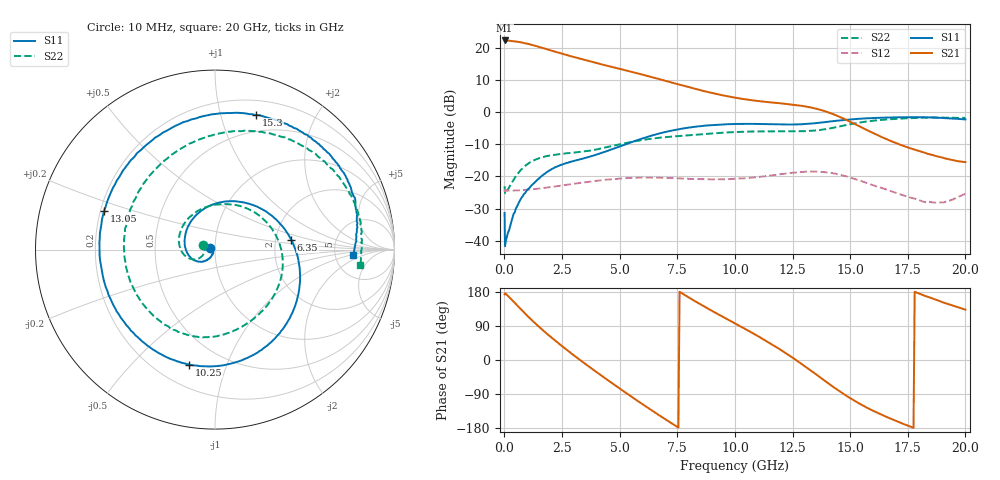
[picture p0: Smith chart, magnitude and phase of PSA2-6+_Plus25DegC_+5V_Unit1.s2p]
!Keysight Technologies,N5242A,MY47200155,A.10.49.08
!Date: Thursday, October 19, 2023 15:15:29
!Correction: S11(Full 2 Port(1,2))
!S21(Full 2 Port(1,2))
!S12(Full 2 Port(1,2))
!S22(Full 2 Port(1,2))
!S2P File: Measurements: S11, S21, S12, S22:
# Hz S  dB  R 50
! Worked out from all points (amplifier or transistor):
!   408 points, 10 MHz to 20 GHz, reference 50 ohm
!   highest |S21| = 22.3 dB at 10 MHz (marker M1)
!   |S21| within 3 dB of that: start of sweep to 1.969 GHz
!   unconditionally stable (mu >= 1): start of sweep to end of sweep
!   at 3.05 GHz: K = 1.07, MAG = 18.0 dB, |S12| = -22.2 dB
!   at 9.85 GHz: K = 1.32, MAG = 9.3 dB, |S12| = -20.8 dB
!   at 20 GHz: K = 7.22, MAG = -6.6 dB, |S12| = -25.4 dB
!   S11 on the Smith chart (normalised r, x): 10 MHz: 0.95, +0.02; 6.35 GHz: 2.44, +0.33; 10.25 GHz: 0.33, -0.75; 13.05 GHz: 0.21, +0.16; 15.3 GHz: 0.33, +1.29; 20 GHz: 7.54, -1.21
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1e7  -31.35 162.3  22.27 173.2  -24.74 -4.6  -23.01 157.6
7e7  -39.74 -163.0  22.22 174.4  -24.42 -1.7  -24.87 -174.5
3.5e8  -32.85 -122.4  22.09 156.8  -24.36 -5.6  -21.64 -152.9
7.5e8  -26.51 -119.2  21.64 131.6  -24.24 -11.4  -17.73 -154.9
1.3e9  -21.98 -130.0  20.69 98.9  -23.90 -20.2  -14.91 -173.1
1.8e9  -18.82 -143.8  19.63 71.7  -23.48 -28.9  -13.72 167.5
2.25e9  -17.02 -160.2  18.68 48.8  -23.03 -37.5  -13.19 149.0
2.75e9  -15.75 178.3  17.65 24.6  -22.54 -48.0  -12.78 127.6
3.35e9  -14.55 150.7  16.46 -3.1  -21.94 -61.7  -12.32 101.5
4e9  -13.20 118.6  15.25 -32.0  -21.35 -77.7  -11.60 74.1
4.7e9  -11.48 82.2  13.99 -62.4  -20.81 -96.2  -10.48 45.8
5.4e9  -9.65 48.0  12.74 -92.1  -20.48 -115.4  -9.42 19.7
6.35e9  -7.38 7.5  10.97 -131.3  -20.34 -141.5  -8.26 -11.9
6.7e9  -6.68 -5.6  10.29 -145.3  -20.38 -150.9  -7.97 -22.6
8.3e9  -4.53 -54.9  7.18 154.2  -20.79 168.3  -7.02 -63.7
1.005e10  -3.68 -97.5  4.44 95.0  -20.68 129.7  -6.19 -96.1
1.025e10  -3.65 -102.5  4.21 88.4  -20.62 125.2  -6.11 -99.8
1.305e10  -3.68 160.7  1.78 -17.0  -18.52 47.5  -5.88 178.3
1.335e10  -3.54 146.9  1.36 -30.3  -18.49 36.9  -5.82 164.4
1.53e10  -2.12 73.1  -4.05 -111.6  -21.02 -31.5  -3.40 77.5
1.67e10  -1.68 44.6  -8.76 -153.4  -24.39 -66.3  -2.23 42.7
2e10  -2.26 -2.4  -15.52 132.9  -25.40 -96.7  -1.80 -6.0
